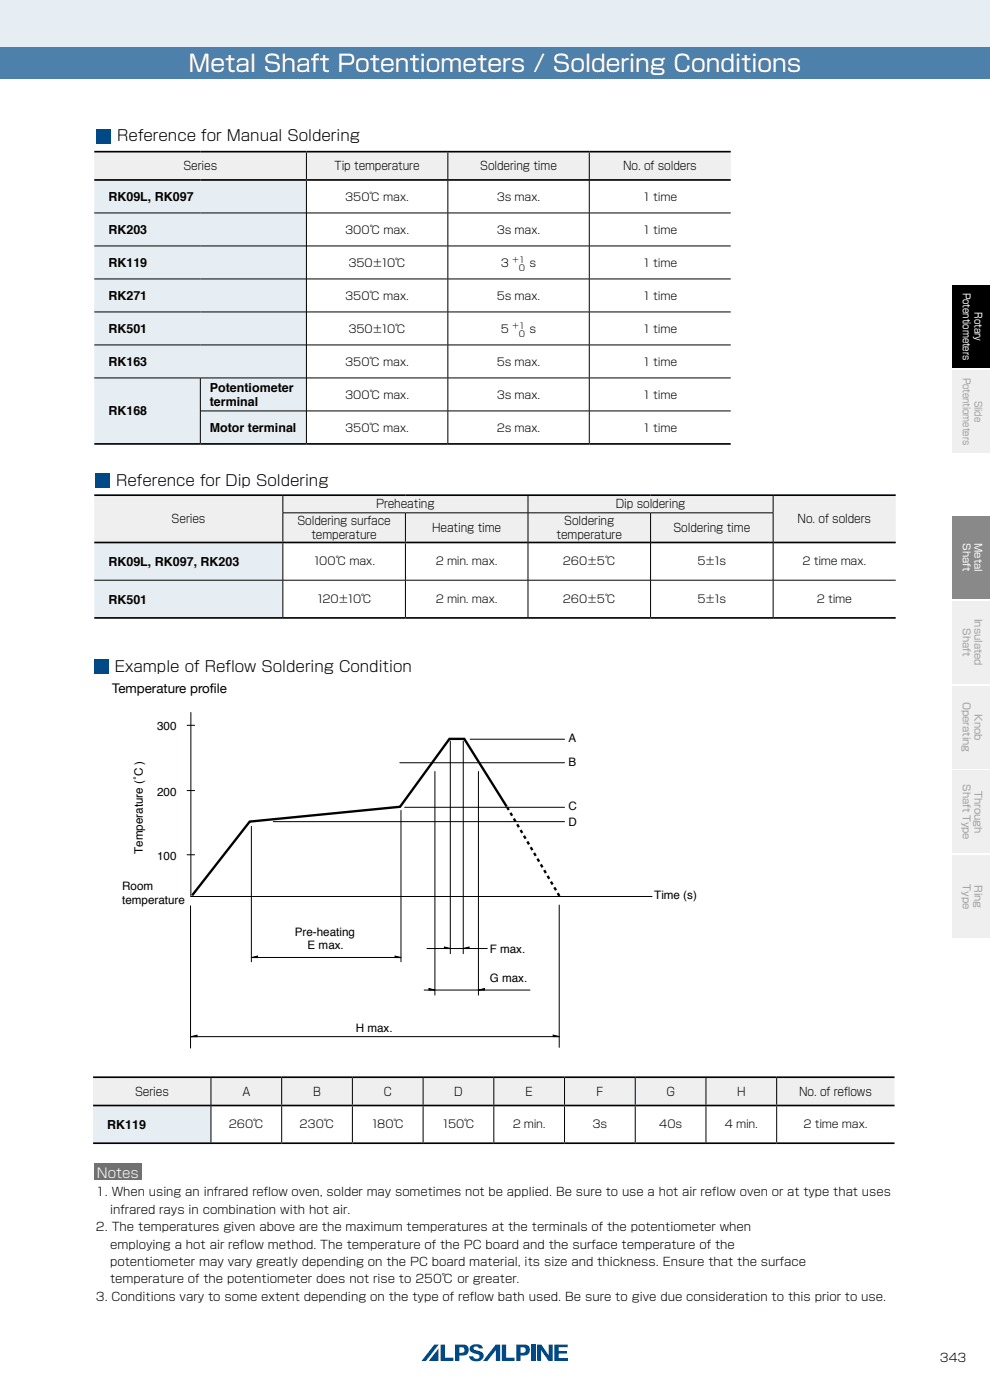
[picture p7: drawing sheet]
<svg xmlns="http://www.w3.org/2000/svg" width="210mm" height="297mm" viewBox="0 0 210 297" stroke-linecap="round" stroke-linejoin="round" font-family="sans-serif">
<defs><g id="words">
<text font-size="4.9" fill="#fff" x="40" y="15.2">Metal Shaft Potentiometers / Soldering Conditions</text>
<g font-size="3.2">
<text x="24.9" y="30">Reference for Manual Soldering</text>
<text x="24.6" y="103">Reference for Dip Soldering</text>
<text x="24.4" y="142.5">Example of Reflow Soldering Condition</text>
</g>
<g font-size="2.8">
<text x="23.8" y="147">Temperature prof</text>
<text x="44.5" y="147">ile</text>
</g>
<text font-size="2.8" fill="#fff" x="20.6" y="249.9">Notes</text>
<g font-size="2.6">
<text x="23" y="42.6">RK09L, RK097</text>
<text x="23" y="49.6">RK203</text>
<text x="23" y="56.6">RK119</text>
<text x="23" y="63.6">RK271</text>
<text x="23" y="70.6">RK501</text>
<text x="23" y="77.6">RK163</text>
<text x="44.5" y="83.2">Potentiometer</text>
<text x="23" y="88.1">RK168</text>
<text x="44.5" y="86">terminal</text>
<text x="44.5" y="91.6">Motor terminal</text>
<text x="23" y="120">RK09L, RK097, RK203</text>
<text x="23" y="128">RK501</text>
<text x="22.7" y="239.5">RK119</text>
</g>
<g font-size="2.5">
<text x="38.9" y="36.1">Series</text>
<text x="71" y="36.1">Tip temperature</text>
<text x="101.9" y="36.1">Soldering time</text>
<text x="132.2" y="36.1">No. of solders</text>
<text x="79.8" y="107.9">Preheating</text>
<text x="130.6" y="107.9">Dip soldering</text>
<text x="36.4" y="111">Series</text>
<text x="63.1" y="111.5">Soldering surface</text>
<text x="91.7" y="112.9">Heating time</text>
<text x="119.7" y="111.5">Soldering</text>
<text x="142.9" y="112.9">Soldering time</text>
<text x="169.2" y="111">No. of solders</text>
<text x="66.1" y="114.3">temperature</text>
<text x="118.1" y="114.3">temperature</text>
<text x="33.3" y="154.9">300</text>
<text x="120.6" y="157.3">A</text>
<text x="120.6" y="162.5">B</text>
<text x="33.3" y="168.8">200</text>
<text x="120.6" y="171.9">C</text>
<text x="120.6" y="175.2">D</text>
<text x="30.3" y="181.2" transform="rotate(-90 30.3 181.2)">Temperature (˚C )</text>
<text x="33.3" y="182.5">100</text>
<text x="25.9" y="188.9">Room</text>
<text x="25.9" y="191.9">temperature</text>
<text x="138.8" y="190.7">Time (s)</text>
<text x="62.5" y="198.5">Pre-heating</text>
<text x="65.3" y="201.3">E max.</text>
<text x="103.9" y="202.3">F max.</text>
<text x="103.9" y="208.4">G max.</text>
<text x="75.5" y="218.8">H max.</text>
<text x="28.7" y="232.5">Series</text>
<text x="51.4" y="232.5">A</text>
<text x="66.4" y="232.5">B</text>
<text x="81.4" y="232.5">C</text>
<text x="96.3" y="232.5">D</text>
<text x="111.5" y="232.5">E</text>
<text x="126.5" y="232.5">F</text>
<text x="141.3" y="232.5">G</text>
<text x="156.3" y="232.5">H</text>
<text x="169.5" y="232.5">No. of reflows</text>
<text x="20.4" y="253.7">1. When using an infrared reflow oven, solder may sometimes not be applied. Be sure to use a hot air reflow oven or at type that uses</text>
<text x="23.4" y="257.5">infrared rays in combination with hot air.</text>
<text x="20.4" y="261.2">2. The temperatures given above are the maximum temperatures at the terminals of the potentiometer when</text>
<text x="23.4" y="264.9">employing a hot air reflow method. The temperature of the PC board and the surface temperature of the</text>
<text x="23.4" y="268.6">potentiometer may vary greatly depending on the PC board material, its size and thickness. Ensure that the surface</text>
<text x="20.3" y="276">3. Conditions vary to some extent depending on the type of reflow bath used. Be sure to give due consideration to this prior to use.</text>
<text x="23.4" y="272.3">temperature of the potentiometer does not rise to 250℃ or greater.</text>
<text x="199.4" y="289">343</text>
</g>
<g font-size="2.3">
<text x="73.2" y="42.5">350℃ max.</text>
<text x="105.4" y="42.5">3s max.</text>
<text x="136.3" y="42.5">1 time</text>
<text x="73.2" y="49.5">300℃ max.</text>
<text x="105.4" y="49.5">3s max.</text>
<text x="136.3" y="49.5">1 time</text>
<text x="73.9" y="56.5">350±10℃</text>
<text x="106.2" y="56.5">3 　 s</text>
<text x="136.3" y="56.5">1 time</text>
<text x="73.2" y="63.5">350℃ max.</text>
<text x="105.4" y="63.5">5s max.</text>
<text x="136.3" y="63.5">1 time</text>
<text x="73.9" y="70.5">350±10℃</text>
<text x="106.2" y="70.5">5 　 s</text>
<text x="136.3" y="70.5">1 time</text>
<text x="73.2" y="77.5">350℃ max.</text>
<text x="105.4" y="77.5">5s max.</text>
<text x="136.3" y="77.5">1 time</text>
<text x="73.2" y="84.5">300℃ max.</text>
<text x="105.4" y="84.5">3s max.</text>
<text x="136.3" y="84.5">1 time</text>
<text x="73.2" y="91.5">350℃ max.</text>
<text x="105.4" y="91.5">2s max.</text>
<text x="136.3" y="91.5">1 time</text>
<text x="66.3" y="120">100℃ max.</text>
<text x="92.5" y="120">2 min. max.</text>
<text x="119.4" y="120">260±5℃</text>
<text x="147.9" y="120">5±1s</text>
<text x="170.2" y="120">2 time max.</text>
<text x="67" y="128">120±10℃</text>
<text x="92.5" y="128">2 min. max.</text>
<text x="119.4" y="128">260±5℃</text>
<text x="147.9" y="128">5±1s</text>
<text x="173.3" y="128">2 time</text>
<text x="48.5" y="239.4">260℃</text>
<text x="63.5" y="239.4">230℃</text>
<text x="78.7" y="239.4">180℃</text>
<text x="93.7" y="239.4">150℃</text>
<text x="108.8" y="239.4">2 min.</text>
<text x="125.7" y="239.4">3s</text>
<text x="139.8" y="239.4">40s</text>
<text x="153.8" y="239.4">4 min.</text>
<text x="170.5" y="239.4">2 time max.</text>
</g>
<g font-size="2.1" fill="#fff">
<text x="204.3" y="62.1" transform="rotate(90 204.3 62.1)">Potentiometers</text>
<text x="206.7" y="66.2" transform="rotate(90 206.7 66.2)">Rotary</text>
<text x="204.3" y="115.3" transform="rotate(90 204.3 115.3)">Shaft</text>
<text x="206.7" y="115.2" transform="rotate(90 206.7 115.2)">Metal</text>
</g>
<g font-size="2.1" fill="#9fa0a0">
<text x="204.3" y="80.1" transform="rotate(90 204.3 80.1)">Potentiometers</text>
<text x="206.7" y="85" transform="rotate(90 206.7 85)">Slide</text>
<text x="206.7" y="131.3" transform="rotate(90 206.7 131.3)">Insulated</text>
<text x="204.3" y="133.3" transform="rotate(90 204.3 133.3)">Shaft</text>
<text x="204.3" y="148.9" transform="rotate(90 204.3 148.9)">Operating</text>
<text x="206.7" y="151.5" transform="rotate(90 206.7 151.5)">Knob</text>
<text x="204.3" y="166.3" transform="rotate(90 204.3 166.3)">Shaft Type</text>
<text x="206.7" y="167.8" transform="rotate(90 206.7 167.8)">Through</text>
<text x="204.3" y="187.6" transform="rotate(90 204.3 187.6)">Type</text>
<text x="206.7" y="187.8" transform="rotate(90 206.7 187.8)">Ring</text>
</g>
<g font-size="1.8">
<text x="108.7" y="55.8">+1</text>
<text x="110.1" y="57.6">0</text>
<text x="108.7" y="69.7">+1</text>
<text x="110.1" y="71.5">0</text>
</g>
</g></defs>
<path d="M0 10h210.1v6.7h-210.1z" fill="#4d80ab"/>
<path d="M0 -.1v10.1" fill="none" stroke="#e6edf3" stroke-width=".21"/>
<path d="M0 -.1h210.1v10.1h-210.1z" fill="#e6edf3"/>
<g fill="#004987">
<path d="M92.1 285.2h1l-2.7 3.5h-1z"/>
<path d="M93 286.1v2.6h-2z"/>
<path d="M99.9 285.5a1.65 1.65 0 0 1 2.6 .6h-.9a.57 .57 0 0 0-.6-.5 .57 .57 0 0 0-.5 .6l.3 .2a1.67 1.67 0 0 1 1.8 1.2 1.62 1.62 0 0 1-1.5 1.2 1.62 1.62 0 0 1-1.6-1.1h.9a.66 .66 0 0 0 .7 .6 .66 .66 0 0 0 .6-.7l-.3-.2a1.92 1.92 0 0 1-1.8-1.3z"/>
<path d="M106.5 285.2h.9v2.8h1.7v.7h-2.6z"/>
<path d="M112.7 285.2h.9v3.5h-.9z"/>
<path d="M113.9 285.2h.9l1.6 2.3v-2.3h.8v3.5h-.9l-1.5-2.3v2.3h-.9z"/>
<path d="M117.6 285.2h2.8v.6h-1.9v.8h1.8v.5h-1.8v1h2v.6h-2.9z"/>
<path d="M93.5 285.2h.9v2.8h1.8v.7h-2.7z"/>
<path d="M105.2 285.2h.9v3.5h-.9v-2.3l-1.8 2.3h-.9z"/>
<path d="M97.4 285.8h.5a.59 .59 0 0 1 .6 .6 .59 .59 0 0 1-.7 .6h-.4zM96.5 285.2v3.5h.9v-1.1h.8a1.16 1.16 0 0 0 1.2-1.1 1.16 1.16 0 0 0-1.1-1.3z"/>
<path d="M110.4 285.8h.4a.59 .59 0 0 1 .7 .6 .59 .59 0 0 1-.7 .6h-.4zM109.5 285.2v3.5h.9v-1.1h.7a1.16 1.16 0 0 0 1.3-1.1 1.16 1.16 0 0 0-1.1-1.3z"/>
</g>
<path d="M202 60.5h8.1v17.5h-8.1z" fill="#000"/>
<path d="M202 78.5h8.1v17.5h-8.1z" fill="#efefef"/>
<path d="M202 109.5h8.1v17.5h-8.1z" fill="#898989"/>
<g fill="#efefef">
<path d="M202 127.5h8.1v17.5h-8.1z"/>
<path d="M202 145.5h8.1v17.5h-8.1z"/>
<path d="M202 163.5h8.1v17.5h-8.1z"/>
<path d="M202 181.5h8.1v17.5h-8.1z"/>
</g>
<g fill="#004987">
<path d="M20.5 27.4h3v3h-3z"/>
<path d="M20 139.9h3v3h-3z"/>
<path d="M20.2 100.4h3v3h-3z"/>
</g>
<path d="M107.5 171.1l-9-14.4h-3.2l-10.4 14.5-31.9 3.1-12.2 15.6" fill="none" stroke="#000" stroke-width=".5"/>
<path d="M107.6 171.2l11.1 19" fill="none" stroke="#000" stroke-width=".5" stroke-dasharray=".7 .7" stroke-linecap="butt"/>
<g fill="none" stroke="#000" stroke-width=".21">
<path d="M39.7 153.9h1.6M40.5 151.1v39.1h97.8M95.5 157.2v45.1M98.3 157.2v45.1M99.7 156.8h20.1M39.7 167.7h1.6M53.3 175.3v28.7M58 174.3h61.8M84.8 161.8h35M85.1 171.9v32.1M85.8 171.3h34M92.3 163.7v47.4"/>
<path d="M101.5 163.7v47.4M39.7 181.3h1.6M40.4 192.2v30.1M118.6 192v30.2M40.5 219.9l1.3-.3v.3zM40.6 219.9h78M53.3 203.1l1.3-.3v.3zM53.3 203.1h31.4M83.8 202.8l1.3 .3h-1.3zM90 210h22.4M90.6 201.2h12.8M91 209.7l1.3 .3h-1.3z"/>
<path d="M94.3 200.9l1.3 .3h-1.3zM98.2 201.2l1.3-.3v.3zM101.5 210l1.3-.3v.3zM117.3 219.6l1.3 .3h-1.3z"/>
</g>
<path d="M40.5 219.9l1.3-.3v.3zM53.3 203.1l1.3-.3v.3zM83.8 202.8l1.3 .3h-1.3zM91 209.7l1.3 .3h-1.3zM94.3 200.9l1.3 .3h-1.3zM98.2 201.2l1.3-.3v.3zM101.5 210l1.3-.3v.3zM117.3 219.6l1.3 .3h-1.3z" fill="#000"/>
<path d="M20 32.2h45v6h-45zM65 32.2h30v6h-30zM95 32.2h30v6h-30zM125 32.2h30v6h-30z" fill="#efefef"/>
<path d="M20 38.2h45v7h-45zM20 45.2h45v7h-45zM20 52.2h45v7h-45zM20 59.2h45v7h-45zM20 66.2h45v7h-45zM20 73.2h45v7h-45zM20 80.2h22.5v14h-22.5zM42.5 80.2h22.5v7h-22.5zM42.5 87.2h22.5v7h-22.5z" fill="#e6edf3"/>
<path d="M20 32.2h135M20 38.2h74.9M95.1 38.2h29.8M125.1 38.2h29.9M20 94.2h135" fill="none" stroke="#000" stroke-width=".35"/>
<g fill="none" stroke="#000" stroke-width=".21">
<path d="M65 32.4v5.6M65 38.4v55.6M95 32.4v12.7M125 32.4v12.7M20 45.2h44.9M20 52.2h44.9M20 59.2h44.9M65.1 45.2h89.9M65.1 52.2h89.9M65.1 59.2h89.9M95 45.2v6.9M95 52.2v6.9"/>
<path d="M95 59.2v6.9M125 45.2v6.9M125 52.2v6.9M125 59.2v6.9M20 66.2h44.9M20 73.2h44.9M65.1 66.2h89.9M65.1 73.2h89.9M95 66.2v6.9M95 73.2v6.9M125 66.2v6.9M125 73.2v6.9"/>
<path d="M20 80.2h44.9M42.5 80.2v13.8M42.6 87.2h22.3M65.1 80.2h89.9M65.1 87.2h89.9M95 80.2v6.9M95 87.2v6.8M125 80.2v6.9M125 87.2v6.8"/>
</g>
<path d="M20 105.1h40v10h-40zM60 105.1h52v3.7h-52zM112 105.1h52v3.7h-52zM164 105.1h26v10h-26zM60 108.8h26v6.3h-26zM86 108.8h26v6.3h-26zM112 108.8h26v6.3h-26zM138 108.8h26v6.3h-26z" fill="#efefef"/>
<path d="M20 115.1h40v8h-40zM20 123.1h40v8h-40z" fill="#e6edf3"/>
<path d="M20 105.1h170M20 115.1h91.9M112.1 115.1h25.8M138.1 115.1h25.8M164.1 115.1h25.9M20 131.1h170" fill="none" stroke="#000" stroke-width=".35"/>
<g fill="none" stroke="#000" stroke-width=".21">
<path d="M59.9 108.8h104.2M60 105.2v3.5M60 108.8v6.1M60 115.3v15.6M86 108.8v6.1M86 115.3v7.7M112 105.2v3.5M112 108.8v14.2M138 108.8v14.2M164 105.2v3.5M164 108.8v14.2M20 123.1h39.9"/>
<path d="M60.1 123.1h129.9M86 123.1v7.8M112 123.1v7.8M138 123.1v7.8M164 123.1v7.8"/>
</g>
<path d="M19.7 228.5h25v6h-25zM44.7 228.5h15v6h-15zM59.7 228.5h15.1v6h-15.1zM74.8 228.5h15v6h-15zM89.7 228.5h15v6h-15zM104.7 228.5h15.1v6h-15.1zM119.8 228.5h15v6h-15zM134.7 228.5h15v6h-15zM149.7 228.5h15.1v6h-15.1zM164.8 228.5h25v6h-25z" fill="#efefef"/>
<path d="M19.7 234.5h25v8h-25z" fill="#e6edf3"/>
<g fill="none" stroke="#000" stroke-width=".21">
<path d="M44.7 228.7v13.7M59.7 228.7v5.7M59.7 234.7v7.7M74.7 228.7v5.7M74.7 234.7v7.7M89.7 228.7v5.7M89.7 234.7v7.7M104.7 228.7v5.7M104.7 234.7v7.7M119.7 228.7v5.7M119.7 234.7v7.7M134.7 228.7v5.7"/>
<path d="M134.7 234.7v7.7M149.7 228.7v5.7M149.7 234.7v7.7M164.7 228.7v5.7M164.7 234.7v7.7"/>
</g>
<path d="M19.7 228.5h170M19.7 234.5h25M44.8 234.5h144.9M19.7 242.5h170" fill="none" stroke="#000" stroke-width=".35"/>
<path d="M20 246.9h10v3.5h-10z" fill="#727171"/>
<use href="#words"/>
</svg>
